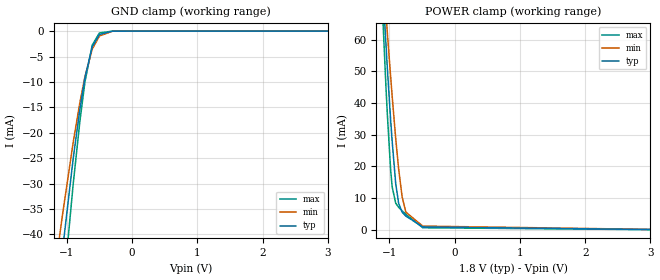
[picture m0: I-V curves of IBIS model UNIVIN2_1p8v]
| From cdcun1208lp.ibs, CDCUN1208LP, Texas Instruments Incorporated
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[Model]   UNIVIN2_1p8v
Model_type   Input
Vinl = 0.7
Vinh = 1.28
|   typ   min   max
C_comp   0.5122pF   0.4546pF   0.5473pF
[Voltage Range]   1.8   1.7   1.9
[Temperature Range]   27   105   -40
[Power Clamp Reference]   1.8   1.7   1.9
[GND Clamp Reference]   -0   -0   0
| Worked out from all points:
|   GND clamp passes 1 mA (typ) near -0.53 V on its own axis
|   POWER clamp passes 1 mA (typ) near -0.49 V on its own axis
[GND Clamp]
|   Voltage   I(typ)   I(min)   I(max)
-1.8V     -156.4mA   -116.4mA   -220.1mA
-1.247V   -65.15mA   -53.62mA   -80mA
-1.162V   -54.47mA   -45.14mA   -66.85mA
-1.076V   -44.19mA   -36.97mA   -54.02mA
-1.053V   -41.58mA   -34.9mA    -50.69mA
-903.1mV  -25.06mA   -21.88mA   -30.09mA
-802mV    -15.49mA   -14.14mA   -17.89mA
-722.8mV  -9.163mA   -8.956mA   -9.961mA
-611.3mV  -3.081mA   -3.545mA   -2.754mA
-500.8mV  -668.3uA   -954.7uA   -356.2uA
-299.8mV  -15.86uA   -18.87uA   -11.97uA
3.595V    0A         0A         0A
[POWER Clamp]
|   Voltage   I(typ)   I(min)   I(max)
-1.8V     353.7mA    299.9mA    440mA
-1.098V   74.62mA    81.18mA    65.8mA
-1.053V   58.76mA    68.31mA    45.32mA
-1.032V   51.23mA    62.33mA    36.8mA
-980.2mV  34.5mA     48.2mA     18.73mA
-956.6mV  27.78mA    42.01mA    13.51mA
-903.1mV  14.63mA    28.84mA    8.463mA
-858mV    8.408mA    19.2mA     7.121mA
-804.9mV  5.591mA    10.48mA    6.037mA
-748mV    4.387mA    5.619mA    4.946mA
-488.4mV  954.5uA    1.222mA    699uA
3.595V    0A         0A         0A
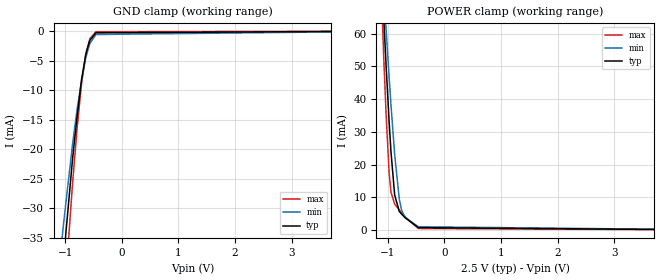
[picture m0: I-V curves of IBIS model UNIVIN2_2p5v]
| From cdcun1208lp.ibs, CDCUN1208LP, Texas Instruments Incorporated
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[Model]   UNIVIN2_2p5v
Model_type   Input
Vinl = 0.88
Vinh = 1.66
|   typ   min   max
C_comp   0.4917pF   0.4455pF   0.5465pF
[Voltage Range]   2.5   2.375   2.625
[Temperature Range]   27   105   -40
[Power Clamp Reference]   2.5   2.375   2.625
[GND Clamp Reference]   0   0   -0
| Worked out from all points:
|   GND clamp passes 1 mA (typ) near -0.53 V on its own axis
|   POWER clamp passes 1 mA (typ) near -0.49 V on its own axis
[GND Clamp]
|   Voltage   I(typ)   I(min)   I(max)
-2.5V     -767.3mA   -657.3mA   -870.9mA
-1.23V    -62.99mA   -51.86mA   -77.48mA
-1.137V   -51.48mA   -42.99mA   -63.09mA
-1.071V   -43.59mA   -36.69mA   -53.29mA
-1.027V   -38.51mA   -32.53mA   -47.1mA
-869.7mV  -21.72mA   -19.21mA   -25.93mA
-789.6mV  -14.54mA   -13.31mA   -16.54mA
-710.4mV  -8.241mA   -8.418mA   -8.903mA
-634.1mV  -3.92mA    -4.439mA   -3.786mA
-563.8mV  -1.572mA   -2.099mA   -1.295mA
-457.6mV  -296.7uA   -582.8uA   -105.8uA
4.992V    0A         0A         0A
[POWER Clamp]
|   Voltage   I(typ)   I(min)   I(max)
-2.5V     643.1mA    526.7mA    828.8mA
-1.098V   75.13mA    81.61mA    66.48mA
-1.071V   65.53mA    73.77mA    53.55mA
-1.027V   50.09mA    61.17mA    35.14mA
-973.6mV  32.96mA    46.74mA    17.39mA
-940.5mV  23.75mA    38.07mA    11.53mA
-875.9mV  10.69mA    23.04mA    7.901mA
-794.5mV  5.672mA    9.449mA    6.124mA
-751.4mV  4.807mA    5.96mA     5.199mA
-689mV    3.7mA      3.802mA    3.997mA
-457.6mV  705uA      983.3uA    442uA
4.992V    0A         0A         0A
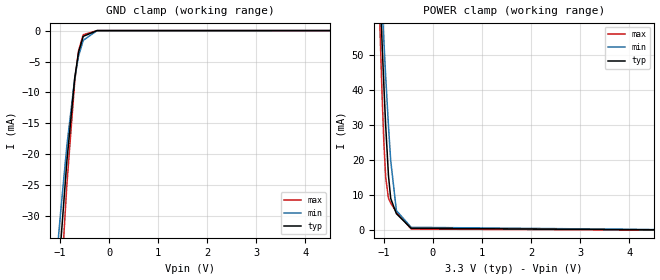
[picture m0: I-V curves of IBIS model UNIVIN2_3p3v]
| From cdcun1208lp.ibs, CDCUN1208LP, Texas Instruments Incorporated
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[Model]   UNIVIN2_3p3v
Model_type   Input
Vinl = 1.1
Vinh = 2.1
|   typ   min   max
C_comp   0.4214pF   0.3947pF   0.5014pF
[Voltage Range]   3.3   2.97   3.63
[Temperature Range]   27   105   -40
[Power Clamp Reference]   3.3   2.97   3.63
[GND Clamp Reference]   -0   0   0
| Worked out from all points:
|   GND clamp passes 1 mA (typ) near -0.53 V on its own axis
|   POWER clamp passes 1 mA (typ) near -0.48 V on its own axis
[GND Clamp]
|   Voltage   I(typ)   I(min)   I(max)
-3.3V     -1.546A    -1.428A    -1.656A
-1.19V    -57.95mA   -48mA      -71.23mA
-1.141V   -52.03mA   -43.18mA   -63.77mA
-1.094V   -46.23mA   -38.83mA   -56.69mA
-1.069V   -43.49mA   -36.61mA   -53.07mA
-1.001V   -35.8mA    -30.4mA    -43.3mA
-861.4mV  -21.07mA   -18.57mA   -24.84mA
-700.7mV  -7.6mA     -7.665mA   -8.123mA
-623.8mV  -3.498mA   -4.124mA   -3.291mA
-529mV    -932.2uA   -1.58mA    -671.1uA
-246.8mV  -3.667uA   -4.468uA   -1.555uA
6.59V     0A         0A         0A
[POWER Clamp]
|   Voltage   I(typ)   I(min)   I(max)
-3.3V     976.4mA    788mA      1.276A
-1.141V   91.52mA    94.33mA    87.32mA
-1.094V   73.63mA    80.47mA    64.6mA
-1.069V   65.07mA    73.38mA    52.98mA
-1.036V   53.35mA    63.67mA    38.58mA
-1.001V   41.61mA    54.24mA    25.53mA
-962.3mV  29.77mA    43.72mA    15.11mA
-905.9mV  15.65mA    29.75mA    9.163mA
-860.3mV  9.107mA    19.89mA    7.799mA
-744.6mV  4.779mA    5.663mA    5.252mA
-443mV    625.1uA    902.3uA    393.8uA
6.59V     0A         0A         0A
